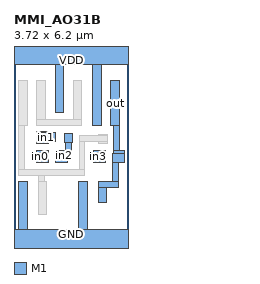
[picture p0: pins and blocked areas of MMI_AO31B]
MACRO MMI_AO31B
	CLASS CORE ;
	FOREIGN MMI_AO31B 0 0 ;
	SIZE 3.72 BY 6.2 ;
	SYMMETRY X Y ;
	SITE CORE1 ;
	PIN out
		DIRECTION output ;
		USE SIGNAL ;
		PORT
			LAYER M1 ;
			RECT 3.165 3.8 3.445 5.27 ;
			LAYER M1 ;
			RECT 3.25 2.98 3.445 3.8 ;
			LAYER M1 ;
			RECT 3.25 2.885 3.6 2.98 ;
			LAYER M1 ;
			RECT 3.22 2.6 3.6 2.885 ;
			LAYER M1 ;
			RECT 3.22 1.98 3.415 2.6 ;
			LAYER M1 ;
			RECT 2.84 1.975 3.415 1.98 ;
			LAYER M1 ;
			RECT 2.75 1.785 3.415 1.975 ;
			LAYER M1 ;
			RECT 2.75 1.275 3.03 1.785 ;
		END
		AntennaDiffArea 0.91245 ;
	END out
	PIN in1
		DIRECTION input ;
		USE SIGNAL ;
		PORT
			LAYER M1 ;
			RECT 0.74 3.56 1.12 3.6 ;
			LAYER M1 ;
			RECT 0.74 3.28 1.345 3.56 ;
			LAYER M1 ;
			RECT 0.74 3.27 1.33 3.28 ;
			LAYER M1 ;
			RECT 0.74 3.22 1.12 3.27 ;
		END
		AntennaGateArea 0.40425 ;
	END in1
	PIN GND
		DIRECTION inout ;
		USE GROUND ;
		PORT
			LAYER M1 ;
			RECT 0.16 0.42 0.44 1.975 ;
			LAYER M1 ;
			RECT 2.12 0.42 2.4 1.975 ;
			LAYER M1 ;
			RECT 0 -0.42 3.72 0.42 ;
		END
	END GND
	PIN in2
		DIRECTION input ;
		USE SIGNAL ;
		PORT
			LAYER M1 ;
			RECT 1.645 3.245 1.925 3.525 ;
			LAYER M1 ;
			RECT 1.695 2.98 1.89 3.245 ;
			LAYER M1 ;
			RECT 1.36 2.695 1.89 2.98 ;
			LAYER M1 ;
			RECT 1.36 2.6 1.74 2.695 ;
		END
		AntennaGateArea 0.40425 ;
	END in2
	PIN VDD
		DIRECTION inout ;
		USE POWER ;
		PORT
			LAYER M1 ;
			RECT 0 5.78 3.72 6.62 ;
			LAYER M1 ;
			RECT 1.34 4.21 1.62 5.78 ;
			LAYER M1 ;
			RECT 2.575 3.8 2.855 5.78 ;
		END
	END VDD
	PIN in3
		DIRECTION input ;
		USE SIGNAL ;
		PORT
			LAYER M1 ;
			RECT 2.6 2.93 2.98 2.98 ;
			LAYER M1 ;
			RECT 2.515 2.65 2.98 2.93 ;
			LAYER M1 ;
			RECT 2.6 2.6 2.98 2.65 ;
		END
		AntennaGateArea 0.40425 ;
	END in3
	PIN in0
		DIRECTION input ;
		USE SIGNAL ;
		PORT
			LAYER M1 ;
			RECT 0.74 2.93 1.12 2.98 ;
			LAYER M1 ;
			RECT 0.555 2.65 1.12 2.93 ;
			LAYER M1 ;
			RECT 0.74 2.6 1.12 2.65 ;
		END
		AntennaGateArea 0.28875 ;
	END in0
	OBS
		LAYER M1 ;
		RECT 0.16 3.8 0.44 5.27 ;
		LAYER M1 ;
		RECT 0.75 3.995 1.03 5.27 ;
		LAYER M1 ;
		RECT 1.93 3.995 2.21 5.27 ;
		LAYER M1 ;
		RECT 0.75 3.8 2.21 3.995 ;
		LAYER M1 ;
		RECT 0.16 2.375 0.355 3.8 ;
		LAYER M1 ;
		RECT 2.755 3.465 3.035 3.51 ;
		LAYER M1 ;
		RECT 2.125 3.27 3.035 3.465 ;
		LAYER M1 ;
		RECT 2.125 2.375 2.315 3.27 ;
		LAYER M1 ;
		RECT 2.755 3.23 3.035 3.27 ;
		LAYER M1 ;
		RECT 0.16 2.185 2.315 2.375 ;
		LAYER M1 ;
		RECT 0.795 1.975 0.985 2.185 ;
		LAYER M1 ;
		RECT 0.79 0.89 1.07 1.975 ;
	END
END MMI_AO31B
